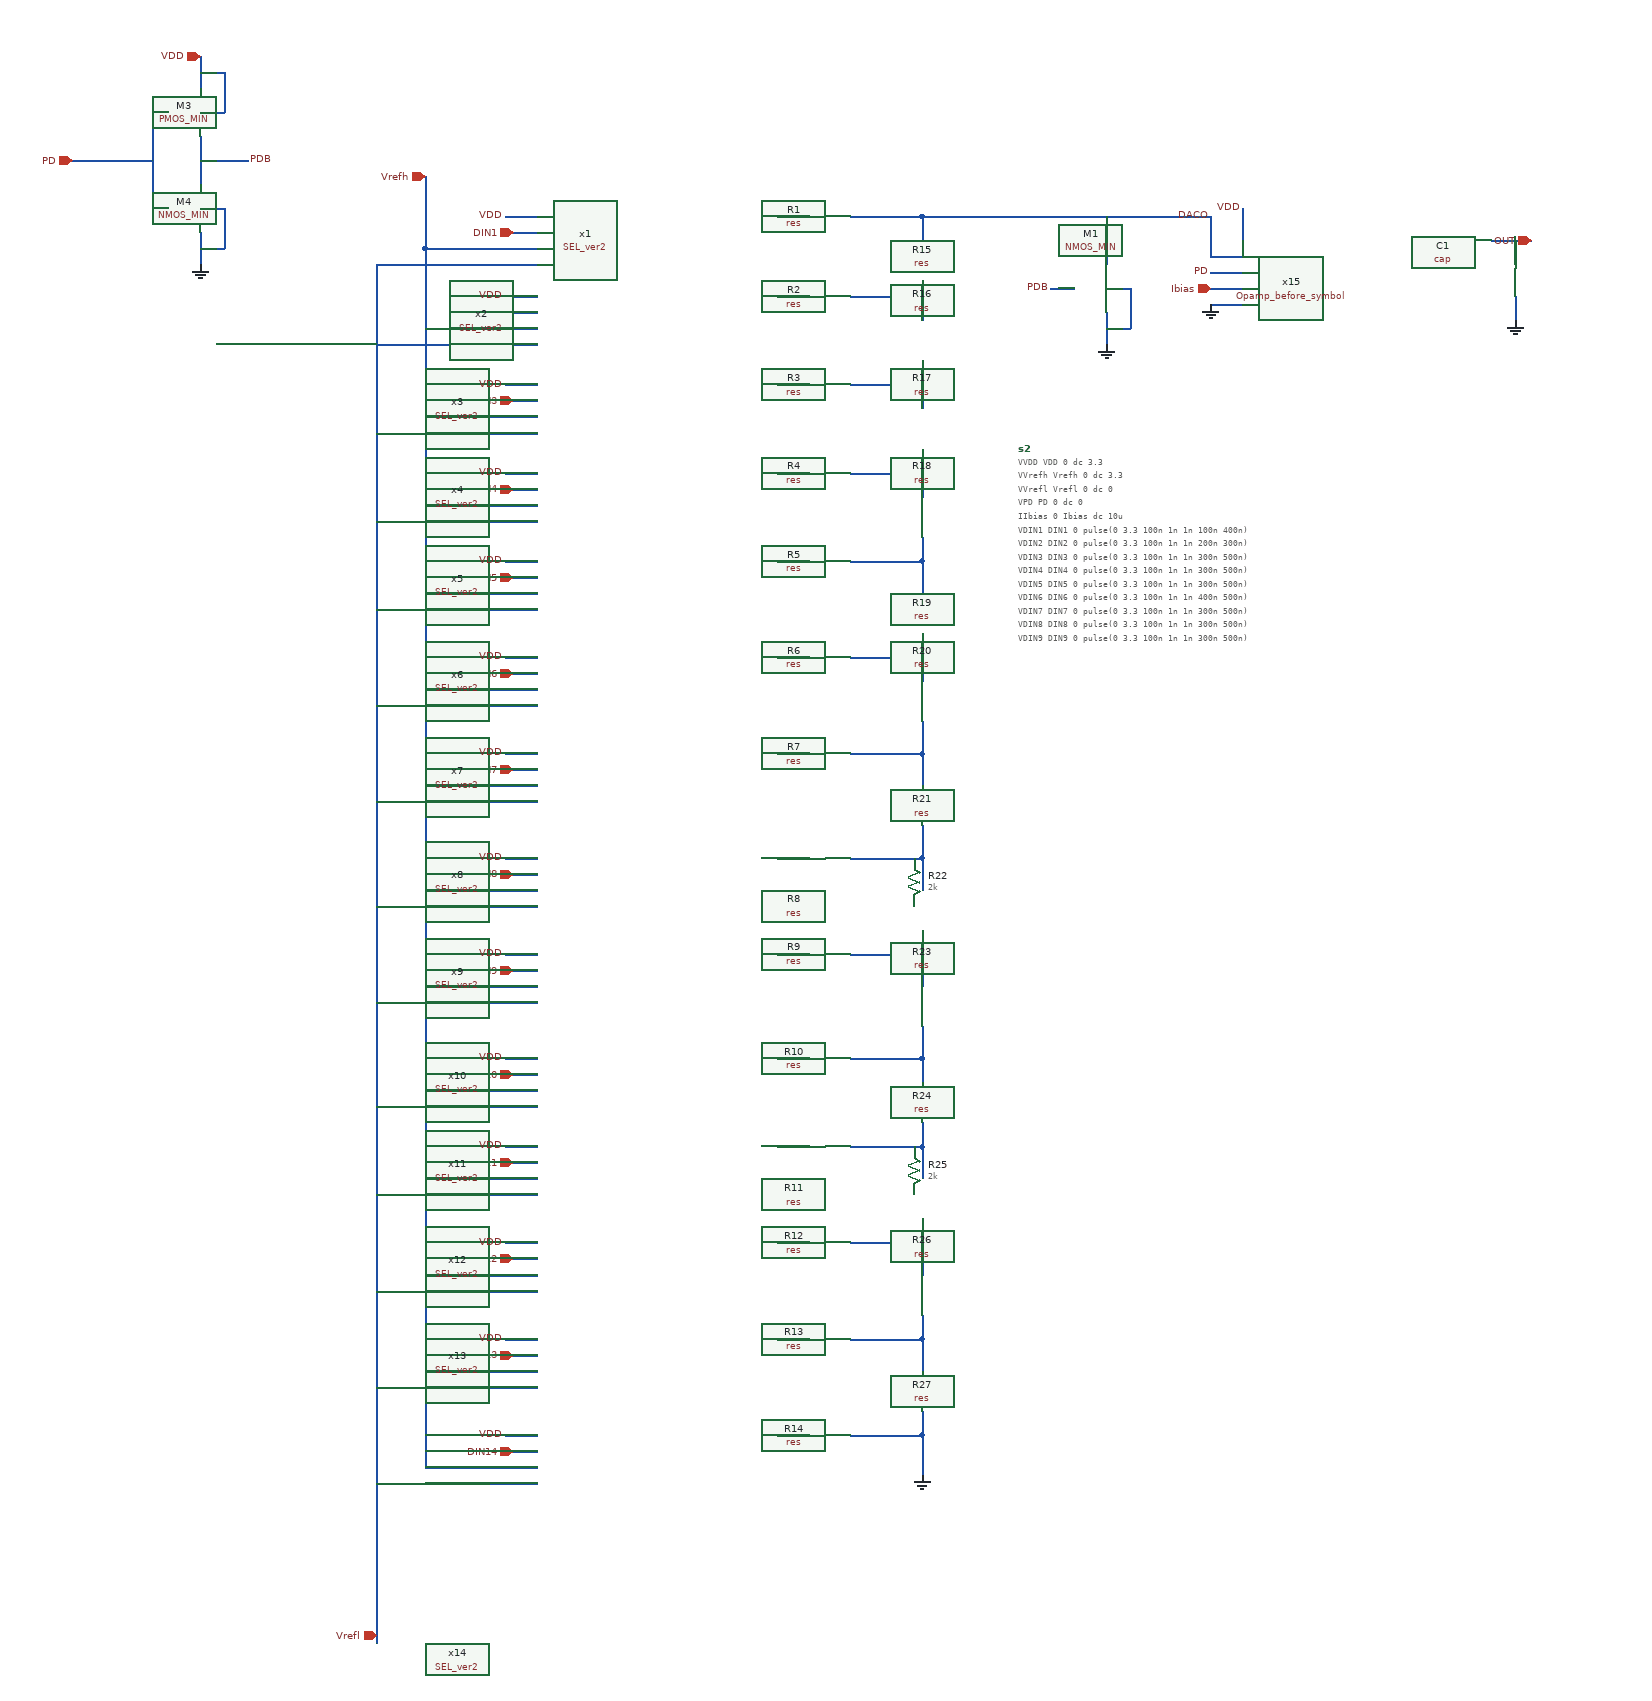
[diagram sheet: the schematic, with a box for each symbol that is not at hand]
v {xschem version=3.4.8RC file_version=1.3}
G {}
K {}
V {}
S {}
F {}
E {}
N 50 -100 140 -100 {lab=DACO}
N 50 0 140 0 {lab=#net1}
N -40 -100 -0 -100 {lab=#net2}
N -40 -0 0 0 {lab=#net3}
N -40 110 -0 110 {lab=#net4}
N -40 220 -0 220 {lab=#net5}
N -40 330 -0 330 {lab=#net6}
N -40 450 -0 450 {lab=#net7}
N -40 570 -0 570 {lab=#net8}
N -40 700 0 700 {lab=#net9}
N -40 820 -0 820 {lab=#net10}
N -40 950 -0 950 {lab=#net11}
N -40 1060 -0 1060 {lab=#net12}
N -40 1180 -0 1180 {lab=#net13}
N -40 1300 -0 1300 {lab=#net14}
N -40 1420 -0 1420 {lab=#net15}
N -480 -60 -340 -60 {lab=Vrefh}
N -480 -60 -480 1460 {lab=Vrefh}
N -480 1460 -340 1460 {lab=Vrefh}
N -480 1340 -340 1340 {lab=Vrefh}
N -480 1220 -340 1220 {lab=Vrefh}
N -480 1100 -340 1100 {lab=Vrefh}
N -480 990 -340 990 {lab=Vrefh}
N -480 860 -340 860 {lab=Vrefh}
N -480 740 -340 740 {lab=Vrefh}
N -480 610 -340 610 {lab=Vrefh}
N -480 490 -340 490 {lab=Vrefh}
N -480 370 -340 370 {lab=Vrefh}
N -480 260 -340 260 {lab=Vrefh}
N -480 150 -340 150 {lab=Vrefh}
N -480 40 -340 40 {lab=Vrefh}
N -540 -40 -340 -40 {lab=Vrefl}
N -540 1480 -340 1480 {lab=Vrefl}
N -540 1360 -340 1360 {lab=Vrefl}
N -540 1240 -340 1240 {lab=Vrefl}
N -540 1120 -340 1120 {lab=Vrefl}
N -540 1010 -340 1010 {lab=Vrefl}
N -540 880 -340 880 {lab=Vrefl}
N -540 760 -340 760 {lab=Vrefl}
N -540 630 -340 630 {lab=Vrefl}
N -540 510 -340 510 {lab=Vrefl}
N -540 390 -340 390 {lab=Vrefl}
N -540 280 -340 280 {lab=Vrefl}
N -540 170 -340 170 {lab=Vrefl}
N -540 60 -340 60 {lab=Vrefl}
N 500 -50 540 -50 {lab=DACO}
N 140 -100 280 -100 {lab=DACO}
N -370 -80 -340 -80 {lab=DIN1}
N -370 20 -340 20 {lab=DIN2}
N -370 130 -340 130 {lab=DIN3}
N -370 240 -340 240 {lab=DIN4}
N -370 350 -340 350 {lab=DIN5}
N -370 470 -340 470 {lab=DIN6}
N -370 590 -340 590 {lab=DIN7}
N -370 720 -340 720 {lab=DIN8}
N -370 840 -340 840 {lab=DIN9}
N -370 970 -340 970 {lab=DIN10}
N -370 1080 -340 1080 {lab=DIN11}
N -370 1200 -340 1200 {lab=DIN12}
N -370 1320 -340 1320 {lab=DIN13}
N -370 1440 -340 1440 {lab=DIN14}
N 500 -100 500 -50 {lab=DACO}
N 140 -100 140 -70 {lab=DACO}
N 140 -20 140 -0 {lab=#net1}
N 50 110 140 110 {lab=#net16}
N 140 90 140 110 {lab=#net16}
N 140 0 140 30 {lab=#net1}
N 140 80 140 90 {lab=#net16}
N 50 220 140 220 {lab=#net17}
N 140 110 140 140 {lab=#net16}
N 140 190 140 220 {lab=#net17}
N 50 330 140 330 {lab=#net18}
N 140 220 140 250 {lab=#net17}
N 140 300 140 330 {lab=#net18}
N 50 450 140 450 {lab=#net19}
N 50 570 140 570 {lab=#net20}
N 50 700 130 700 {lab=#net21}
N 130 700 140 700 {lab=#net21}
N 140 330 140 370 {lab=#net18}
N 140 420 140 450 {lab=#net19}
N 140 450 140 480 {lab=#net19}
N 140 530 140 570 {lab=#net20}
N 140 570 140 610 {lab=#net20}
N 140 660 140 700 {lab=#net21}
N 140 700 140 740 {lab=#net21}
N 50 820 140 820 {lab=#net22}
N 140 790 140 820 {lab=#net22}
N 50 950 130 950 {lab=#net23}
N 50 1060 130 1060 {lab=#net24}
N 130 950 140 950 {lab=#net23}
N 130 1060 140 1060 {lab=#net24}
N 50 1180 140 1180 {lab=#net25}
N 140 820 140 860 {lab=#net22}
N 140 910 140 950 {lab=#net23}
N 140 950 140 980 {lab=#net23}
N 140 1030 140 1060 {lab=#net24}
N 140 1060 140 1100 {lab=#net24}
N 140 1150 140 1180 {lab=#net25}
N 50 1300 140 1300 {lab=#net26}
N 50 1420 140 1420 {lab=GND}
N 140 1180 140 1220 {lab=#net25}
N 140 1270 140 1300 {lab=#net26}
N 140 1300 140 1340 {lab=#net26}
N 140 1390 140 1420 {lab=GND}
N 140 1420 140 1470 {lab=GND}
N -760 -80 -760 -40 {lab=GND}
N -760 -110 -730 -110 {lab=GND}
N -730 -110 -730 -60 {lab=GND}
N -760 -60 -730 -60 {lab=GND}
N -760 -200 -760 -140 {lab=PDB}
N -760 -170 -720 -170 {lab=PDB}
N -820 -230 -800 -230 {lab=PD}
N -820 -230 -820 -110 {lab=PD}
N -820 -110 -800 -110 {lab=PD}
N -920 -170 -820 -170 {lab=PD}
N -760 -300 -760 -260 {lab=VDD}
N -760 -280 -730 -280 {lab=VDD}
N -730 -280 -730 -230 {lab=VDD}
N -760 -230 -730 -230 {lab=VDD}
N -380 -100 -340 -100 {lab=VDD}
N -380 1420 -340 1420 {lab=VDD}
N -380 1300 -340 1300 {lab=VDD}
N -480 -150 -480 -60 {lab=Vrefh}
N -380 1180 -340 1180 {lab=VDD}
N -380 1060 -340 1060 {lab=VDD}
N -380 950 -340 950 {lab=VDD}
N -380 820 -340 820 {lab=VDD}
N -380 700 -340 700 {lab=VDD}
N -380 570 -340 570 {lab=VDD}
N -380 450 -340 450 {lab=VDD}
N -380 330 -340 330 {lab=VDD}
N -380 220 -340 220 {lab=VDD}
N -380 110 -340 110 {lab=VDD}
N -380 0 -340 0 {lab=VDD}
N -540 110 -540 1680 {lab=Vrefl}
N 850 -70 900 -70 {lab=OUT}
N 540 -110 540 -70 {lab=VDD}
N 500 -10 540 -10 {lab=Ibias}
N 500 10 540 10 {lab=GND}
N 500 -30 540 -30 {lab=PD}
N 880 -70 880 -40 {lab=OUT}
N 880 0 880 30 {lab=GND}
N -540 -40 -540 110 {lab=Vrefl}
N 280 -100 360 -100 {lab=DACO}
N -720 -170 -700 -170 {lab=PDB}
N 360 -100 500 -100 {lab=DACO}
N 370 -100 370 -40 {lab=DACO}
N 370 20 370 60 {lab=GND}
N 370 -10 400 -10 {lab=GND}
N 400 -10 400 40 {lab=GND}
N 370 40 400 40 {lab=GND}
N 300 -10 330 -10 {lab=PDB}
C {res.sym} 60 -110 1 0 {name=R1
value=4k
footprint=1206
device=resistor
m=1}
C {res.sym} 130 -80 0 0 {name=R15
value=2k
footprint=1206
device=resistor
m=1}
C {ipin.sym} -480 -150 1 0 {name=p1 lab=Vrefh}
C {ipin.sym} -540 1670 3 0 {name=p2 lab=Vrefl}
C {iopin.sym} 900 -70 0 0 {name=p3 lab=OUT}
C {ipin.sym} -370 -80 0 0 {name=p4 lab=DIN1}
C {ipin.sym} -370 20 0 0 {name=p6 lab=DIN2}
C {ipin.sym} -370 130 0 0 {name=p7 lab=DIN3}
C {ipin.sym} -370 240 0 0 {name=p8 lab=DIN4}
C {ipin.sym} -370 350 0 0 {name=p9 lab=DIN5}
C {ipin.sym} -370 470 0 0 {name=p10 lab=DIN6}
C {ipin.sym} -370 590 0 0 {name=p11 lab=DIN7}
C {ipin.sym} -370 720 0 0 {name=p12 lab=DIN8}
C {ipin.sym} -370 840 0 0 {name=p13 lab=DIN9}
C {ipin.sym} -370 970 0 0 {name=p14 lab=DIN10}
C {ipin.sym} -370 1080 0 0 {name=p15 lab=DIN11}
C {ipin.sym} -370 1200 0 0 {name=p16 lab=DIN12}
C {ipin.sym} -370 1320 0 0 {name=p17 lab=DIN13}
C {ipin.sym} -370 1440 0 0 {name=p18 lab=DIN14}
C {code_shown.sym} 260 190 0 0 {name=s2 only_toplevel=false value=
"
VVDD VDD 0 dc 3.3
VVrefh Vrefh 0 dc 3.3
VVrefl Vrefl 0 dc 0
VPD PD 0 dc 0
IIbias 0 Ibias dc 10u

VDIN1 DIN1 0 pulse(0 3.3 100n 1n 1n 100n 400n)
VDIN2 DIN2 0 pulse(0 3.3 100n 1n 1n 200n 300n)
VDIN3 DIN3 0 pulse(0 3.3 100n 1n 1n 300n 500n)
VDIN4 DIN4 0 pulse(0 3.3 100n 1n 1n 300n 500n)
VDIN5 DIN5 0 pulse(0 3.3 100n 1n 1n 300n 500n)
VDIN6 DIN6 0 pulse(0 3.3 100n 1n 1n 400n 500n)
VDIN7 DIN7 0 pulse(0 3.3 100n 1n 1n 300n 500n)
VDIN8 DIN8 0 pulse(0 3.3 100n 1n 1n 300n 500n)
VDIN9 DIN9 0 pulse(0 3.3 100n 1n 1n 300n 500n)
VDIN10 DIN10 0 pulse(0 3.3 100n 1n 1n 400n 500n)
VDIN11 DIN11 0 pulse(0 3.3 100n 1n 1n 300n 500n)
VDIN12 DIN12 0 pulse(0 3.3 100n 1n 1n 300n 500n)
VDIN13 DIN13 0 pulse(0 3.3 100n 1n 1n 300n 500n)
VDIN14 DIN14 0 pulse(0 3.3 100n 1n 1n 400n 500n)

.meas tran IAVG AVG I(C1)

.include /home/raidonn/LRCircuit/spicemodel/ocs65_stl_n3_typ.para
.include /home/raidonn/LRCircuit/spicemodel/ocs65_stl_p3_typ.para

.control
save all
tran 1n 500n
plot V(DACO) 
plot V(OUT)

write "RDAC_ver2.raw"

.endc"
}
C {res.sym} 60 -10 1 0 {name=R2
value=4k
footprint=1206
device=resistor
m=1}
C {res.sym} 60 100 1 0 {name=R3
value=4k
footprint=1206
device=resistor
m=1}
C {res.sym} 60 210 1 0 {name=R4
value=4k
footprint=1206
device=resistor
m=1}
C {res.sym} 60 320 1 0 {name=R5
value=4k
footprint=1206
device=resistor
m=1}
C {res.sym} 60 440 1 0 {name=R6
value=4k
footprint=1206
device=resistor
m=1}
C {res.sym} 60 560 1 0 {name=R7
value=4k
footprint=1206
device=resistor
m=1}
C {res.sym} 60 690 1 0 {name=R8
value=4k
footprint=1206
device=resistor
m=1}
C {res.sym} 60 810 1 0 {name=R9
value=4k
footprint=1206
device=resistor
m=1}
C {res.sym} 60 940 1 0 {name=R10
value=4k
footprint=1206
device=resistor
m=1}
C {res.sym} 60 1050 1 0 {name=R11
value=4k
footprint=1206
device=resistor
m=1}
C {res.sym} 60 1170 1 0 {name=R12
value=4k
footprint=1206
device=resistor
m=1}
C {res.sym} 60 1290 1 0 {name=R13
value=4k
footprint=1206
device=resistor
m=1}
C {res.sym} 60 1410 1 0 {name=R14
value=4k
footprint=1206
device=resistor
m=1}
C {res.sym} 130 20 0 0 {name=R16
value=2k
footprint=1206
device=resistor
m=1}
C {res.sym} 130 130 0 0 {name=R17
value=2k
footprint=1206
device=resistor
m=1}
C {res.sym} 130 240 0 0 {name=R18
value=2k
footprint=1206
device=resistor
m=1}
C {res.sym} 130 360 0 0 {name=R19
value=2k
footprint=1206
device=resistor
m=1}
C {res.sym} 130 470 0 0 {name=R20
value=2k
footprint=1206
device=resistor
m=1}
C {res.sym} 130 600 0 0 {name=R21
value=2k
footprint=1206
device=resistor
m=1}
C {res.sym} 130 730 0 0 {name=R22
value=2k
footprint=1206
device=resistor
m=1}
C {res.sym} 130 850 0 0 {name=R23
value=2k
footprint=1206
device=resistor
m=1}
C {res.sym} 130 970 0 0 {name=R24
value=2k
footprint=1206
device=resistor
m=1}
C {res.sym} 130 1090 0 0 {name=R25
value=2k
footprint=1206
device=resistor
m=1}
C {res.sym} 130 1210 0 0 {name=R26
value=2k
footprint=1206
device=resistor
m=1}
C {res.sym} 130 1330 0 0 {name=R27
value=2k
footprint=1206
device=resistor
m=1}
C {gnd.sym} 140 1470 0 0 {name=l1 lab=GND}
C {PMOS_MIN.sym} -800 -230 0 0 {name=M3 model=p3.0 w=3.5u l=0.35u as=0 ps=0 ad=0 pd=0 m=1}
C {NMOS_MIN.sym} -800 -110 0 0 {name=M4 model=n3.0 w=3.5u l=0.35u as=0 ps=0 ad=0 pd=0 m=1}
C {ipin.sym} -920 -170 0 0 {name=p5 lab=PD}
C {gnd.sym} -760 -40 0 0 {name=l2 lab=GND}
C {ipin.sym} -760 -300 1 0 {name=p19 lab=VDD}
C {/home/raidonn/LRCircuit/work3/SEL_ver2.sym} -190 -70 0 0 {name=x1}
C {lab_pin.sym} -380 -100 0 0 {name=l5 sig_type=std_logic lab=VDD}
C {/home/raidonn/LRCircuit/work3/SEL_ver2.sym} -190 30 0 0 {name=x2}
C {/home/raidonn/LRCircuit/work3/SEL_ver2.sym} -190 140 0 0 {name=x3}
C {/home/raidonn/LRCircuit/work3/SEL_ver2.sym} -190 250 0 0 {name=x4}
C {/home/raidonn/LRCircuit/work3/SEL_ver2.sym} -190 360 0 0 {name=x5}
C {/home/raidonn/LRCircuit/work3/SEL_ver2.sym} -190 480 0 0 {name=x6}
C {/home/raidonn/LRCircuit/work3/SEL_ver2.sym} -190 600 0 0 {name=x7}
C {/home/raidonn/LRCircuit/work3/SEL_ver2.sym} -190 730 0 0 {name=x8}
C {/home/raidonn/LRCircuit/work3/SEL_ver2.sym} -190 850 0 0 {name=x9}
C {/home/raidonn/LRCircuit/work3/SEL_ver2.sym} -190 980 0 0 {name=x10}
C {/home/raidonn/LRCircuit/work3/SEL_ver2.sym} -190 1090 0 0 {name=x11}
C {/home/raidonn/LRCircuit/work3/SEL_ver2.sym} -190 1210 0 0 {name=x12}
C {/home/raidonn/LRCircuit/work3/SEL_ver2.sym} -190 1330 0 0 {name=x13}
C {/home/raidonn/LRCircuit/work3/SEL_ver2.sym} -190 1450 0 0 {name=x14}
C {lab_pin.sym} -380 1420 0 0 {name=l6 sig_type=std_logic lab=VDD}
C {lab_pin.sym} -380 1300 0 0 {name=l7 sig_type=std_logic lab=VDD}
C {lab_pin.sym} -380 1180 0 0 {name=l8 sig_type=std_logic lab=VDD}
C {lab_pin.sym} -380 1060 0 0 {name=l9 sig_type=std_logic lab=VDD}
C {lab_pin.sym} -380 950 0 0 {name=l10 sig_type=std_logic lab=VDD}
C {lab_pin.sym} -380 820 0 0 {name=l11 sig_type=std_logic lab=VDD}
C {lab_pin.sym} -380 700 0 0 {name=l12 sig_type=std_logic lab=VDD}
C {lab_pin.sym} -380 570 0 0 {name=l13 sig_type=std_logic lab=VDD}
C {lab_pin.sym} -380 450 0 0 {name=l14 sig_type=std_logic lab=VDD}
C {lab_pin.sym} -380 330 0 0 {name=l15 sig_type=std_logic lab=VDD}
C {lab_pin.sym} -380 220 0 0 {name=l16 sig_type=std_logic lab=VDD}
C {lab_pin.sym} -380 110 0 0 {name=l17 sig_type=std_logic lab=VDD}
C {lab_pin.sym} -380 0 0 0 {name=l18 sig_type=std_logic lab=VDD}
C {lab_pin.sym} 500 -100 1 0 {name=l4 sig_type=std_logic lab=DACO}
C {/home/raidonn/LRCircuit/work3/origin/Opamp_before_symbol.sym} 690 -30 0 0 {name=x15}
C {lab_pin.sym} 540 -110 1 0 {name=l19 sig_type=std_logic lab=VDD}
C {ipin.sym} 500 -10 0 0 {name=p20 lab=Ibias}
C {gnd.sym} 500 10 0 0 {name=l20 lab=GND}
C {lab_pin.sym} 500 -30 0 0 {name=l21 sig_type=std_logic lab=PD}
C {cap.sym} 870 -40 0 0 {name=C1
m=1
value=1f
footprint=1206
device=ceramic}
C {gnd.sym} 880 30 0 0 {name=l22 lab=GND}
C {lab_pin.sym} -700 -170 2 0 {name=l24 sig_type=std_logic lab=PDB}
C {NMOS_MIN.sym} 330 -10 0 0 {name=M1 model=n3.0 w=3.5u l=0.35u as=0 ps=0 ad=0 pd=0 m=1}
C {gnd.sym} 370 60 0 0 {name=l3 lab=GND}
C {lab_pin.sym} 300 -10 0 0 {name=l23 sig_type=std_logic lab=PDB}
